# Generated by FakeRAM 2.0 (routing-friendly)
VERSION 5.7 ;
BUSBITCHARS "[]" ;
PROPERTYDEFINITIONS
  MACRO width INTEGER ;
  MACRO depth INTEGER ;
  MACRO banks INTEGER ;
END PROPERTYDEFINITIONS
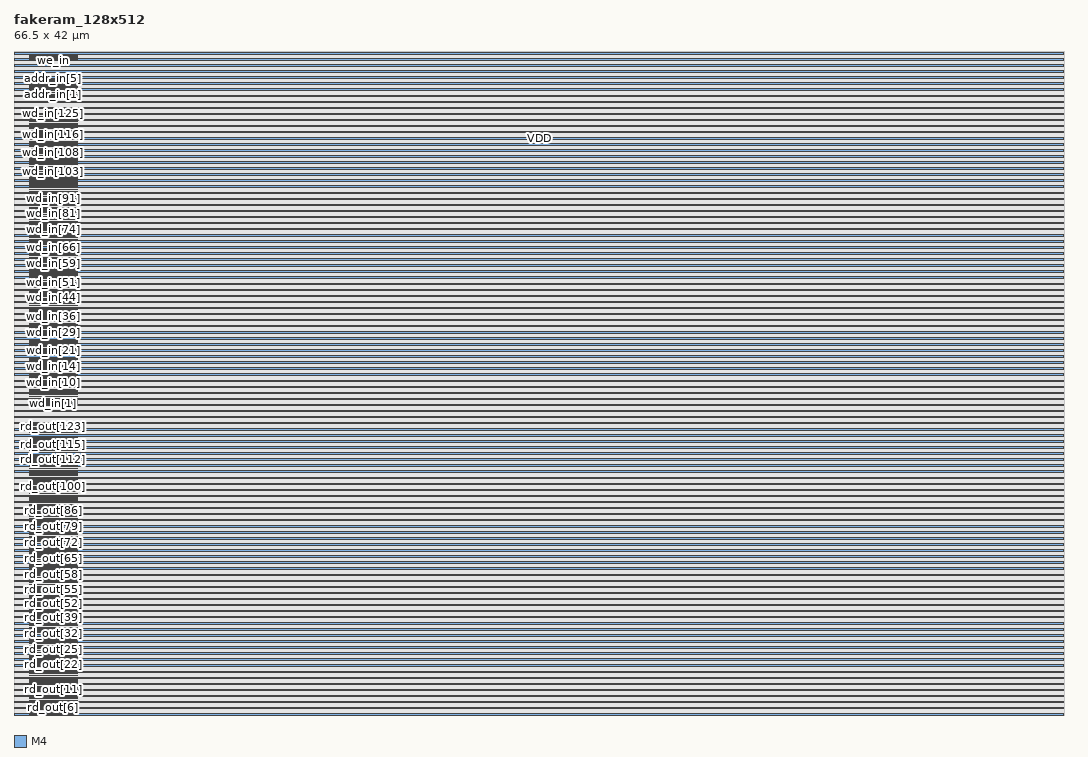
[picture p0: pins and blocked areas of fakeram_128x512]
MACRO fakeram_128x512
  PROPERTY width 128 ;
  PROPERTY depth 512 ;
  PROPERTY banks 4 ;
  FOREIGN fakeram_128x512 0 0 ;
  SYMMETRY X Y R90 ;
  SIZE 66.500 BY 42.000 ;
  CLASS BLOCK ;
  PIN rd_out[0]
    DIRECTION OUTPUT ;
    USE SIGNAL ;
    PORT
      LAYER M4 ;
      RECT 1.000 0.048 3.000 0.072 ;
    END
    PORT
      LAYER M4 ;
      RECT 1.000 0.036 4.000 0.084 ;
    END
  END rd_out[0]
  PIN rd_out[1]
    DIRECTION OUTPUT ;
    USE SIGNAL ;
    PORT
      LAYER M4 ;
      RECT 1.000 0.192 3.000 0.216 ;
    END
    PORT
      LAYER M4 ;
      RECT 1.000 0.180 4.000 0.228 ;
    END
  END rd_out[1]
  PIN rd_out[2]
    DIRECTION OUTPUT ;
    USE SIGNAL ;
    PORT
      LAYER M4 ;
      RECT 1.000 0.336 3.000 0.360 ;
    END
    PORT
      LAYER M4 ;
      RECT 1.000 0.324 4.000 0.372 ;
    END
  END rd_out[2]
  PIN rd_out[3]
    DIRECTION OUTPUT ;
    USE SIGNAL ;
    PORT
      LAYER M4 ;
      RECT 1.000 0.480 3.000 0.504 ;
    END
    PORT
      LAYER M4 ;
      RECT 1.000 0.468 4.000 0.516 ;
    END
  END rd_out[3]
  PIN rd_out[4]
    DIRECTION OUTPUT ;
    USE SIGNAL ;
    PORT
      LAYER M4 ;
      RECT 1.000 0.624 3.000 0.648 ;
    END
    PORT
      LAYER M4 ;
      RECT 1.000 0.612 4.000 0.660 ;
    END
  END rd_out[4]
  PIN rd_out[5]
    DIRECTION OUTPUT ;
    USE SIGNAL ;
    PORT
      LAYER M4 ;
      RECT 1.000 0.768 3.000 0.792 ;
    END
    PORT
      LAYER M4 ;
      RECT 1.000 0.756 4.000 0.804 ;
    END
  END rd_out[5]
  PIN rd_out[6]
    DIRECTION OUTPUT ;
    USE SIGNAL ;
    PORT
      LAYER M4 ;
      RECT 1.000 0.912 3.000 0.936 ;
    END
    PORT
      LAYER M4 ;
      RECT 1.000 0.900 4.000 0.948 ;
    END
  END rd_out[6]
  PIN rd_out[7]
    DIRECTION OUTPUT ;
    USE SIGNAL ;
    PORT
      LAYER M4 ;
      RECT 1.000 1.056 3.000 1.080 ;
    END
    PORT
      LAYER M4 ;
      RECT 1.000 1.044 4.000 1.092 ;
    END
  END rd_out[7]
  PIN rd_out[8]
    DIRECTION OUTPUT ;
    USE SIGNAL ;
    PORT
      LAYER M4 ;
      RECT 1.000 1.200 3.000 1.224 ;
    END
    PORT
      LAYER M4 ;
      RECT 1.000 1.188 4.000 1.236 ;
    END
  END rd_out[8]
  PIN rd_out[9]
    DIRECTION OUTPUT ;
    USE SIGNAL ;
    PORT
      LAYER M4 ;
      RECT 1.000 1.344 3.000 1.368 ;
    END
    PORT
      LAYER M4 ;
      RECT 1.000 1.332 4.000 1.380 ;
    END
  END rd_out[9]
  PIN rd_out[10]
    DIRECTION OUTPUT ;
    USE SIGNAL ;
    PORT
      LAYER M4 ;
      RECT 1.000 1.488 3.000 1.512 ;
    END
    PORT
      LAYER M4 ;
      RECT 1.000 1.476 4.000 1.524 ;
    END
  END rd_out[10]
  PIN rd_out[11]
    DIRECTION OUTPUT ;
    USE SIGNAL ;
    PORT
      LAYER M4 ;
      RECT 1.000 1.632 3.000 1.656 ;
    END
    PORT
      LAYER M4 ;
      RECT 1.000 1.620 4.000 1.668 ;
    END
  END rd_out[11]
  PIN rd_out[12]
    DIRECTION OUTPUT ;
    USE SIGNAL ;
    PORT
      LAYER M4 ;
      RECT 1.000 1.776 3.000 1.800 ;
    END
    PORT
      LAYER M4 ;
      RECT 1.000 1.764 4.000 1.812 ;
    END
  END rd_out[12]
  PIN rd_out[13]
    DIRECTION OUTPUT ;
    USE SIGNAL ;
    PORT
      LAYER M4 ;
      RECT 1.000 1.920 3.000 1.944 ;
    END
    PORT
      LAYER M4 ;
      RECT 1.000 1.908 4.000 1.956 ;
    END
  END rd_out[13]
  PIN rd_out[14]
    DIRECTION OUTPUT ;
    USE SIGNAL ;
    PORT
      LAYER M4 ;
      RECT 1.000 2.064 3.000 2.088 ;
    END
    PORT
      LAYER M4 ;
      RECT 1.000 2.052 4.000 2.100 ;
    END
  END rd_out[14]
  PIN rd_out[15]
    DIRECTION OUTPUT ;
    USE SIGNAL ;
    PORT
      LAYER M4 ;
      RECT 1.000 2.208 3.000 2.232 ;
    END
    PORT
      LAYER M4 ;
      RECT 1.000 2.196 4.000 2.244 ;
    END
  END rd_out[15]
  PIN rd_out[16]
    DIRECTION OUTPUT ;
    USE SIGNAL ;
    PORT
      LAYER M4 ;
      RECT 1.000 2.352 3.000 2.376 ;
    END
    PORT
      LAYER M4 ;
      RECT 1.000 2.340 4.000 2.388 ;
    END
  END rd_out[16]
  PIN rd_out[17]
    DIRECTION OUTPUT ;
    USE SIGNAL ;
    PORT
      LAYER M4 ;
      RECT 1.000 2.496 3.000 2.520 ;
    END
    PORT
      LAYER M4 ;
      RECT 1.000 2.484 4.000 2.532 ;
    END
  END rd_out[17]
  PIN rd_out[18]
    DIRECTION OUTPUT ;
    USE SIGNAL ;
    PORT
      LAYER M4 ;
      RECT 1.000 2.640 3.000 2.664 ;
    END
    PORT
      LAYER M4 ;
      RECT 1.000 2.628 4.000 2.676 ;
    END
  END rd_out[18]
  PIN rd_out[19]
    DIRECTION OUTPUT ;
    USE SIGNAL ;
    PORT
      LAYER M4 ;
      RECT 1.000 2.784 3.000 2.808 ;
    END
    PORT
      LAYER M4 ;
      RECT 1.000 2.772 4.000 2.820 ;
    END
  END rd_out[19]
  PIN rd_out[20]
    DIRECTION OUTPUT ;
    USE SIGNAL ;
    PORT
      LAYER M4 ;
      RECT 1.000 2.928 3.000 2.952 ;
    END
    PORT
      LAYER M4 ;
      RECT 1.000 2.916 4.000 2.964 ;
    END
  END rd_out[20]
  PIN rd_out[21]
    DIRECTION OUTPUT ;
    USE SIGNAL ;
    PORT
      LAYER M4 ;
      RECT 1.000 3.072 3.000 3.096 ;
    END
    PORT
      LAYER M4 ;
      RECT 1.000 3.060 4.000 3.108 ;
    END
  END rd_out[21]
  PIN rd_out[22]
    DIRECTION OUTPUT ;
    USE SIGNAL ;
    PORT
      LAYER M4 ;
      RECT 1.000 3.216 3.000 3.240 ;
    END
    PORT
      LAYER M4 ;
      RECT 1.000 3.204 4.000 3.252 ;
    END
  END rd_out[22]
  PIN rd_out[23]
    DIRECTION OUTPUT ;
    USE SIGNAL ;
    PORT
      LAYER M4 ;
      RECT 1.000 3.360 3.000 3.384 ;
    END
    PORT
      LAYER M4 ;
      RECT 1.000 3.348 4.000 3.396 ;
    END
  END rd_out[23]
  PIN rd_out[24]
    DIRECTION OUTPUT ;
    USE SIGNAL ;
    PORT
      LAYER M4 ;
      RECT 1.000 3.504 3.000 3.528 ;
    END
    PORT
      LAYER M4 ;
      RECT 1.000 3.492 4.000 3.540 ;
    END
  END rd_out[24]
  PIN rd_out[25]
    DIRECTION OUTPUT ;
    USE SIGNAL ;
    PORT
      LAYER M4 ;
      RECT 1.000 3.648 3.000 3.672 ;
    END
    PORT
      LAYER M4 ;
      RECT 1.000 3.636 4.000 3.684 ;
    END
  END rd_out[25]
  PIN rd_out[26]
    DIRECTION OUTPUT ;
    USE SIGNAL ;
    PORT
      LAYER M4 ;
      RECT 1.000 3.792 3.000 3.816 ;
    END
    PORT
      LAYER M4 ;
      RECT 1.000 3.780 4.000 3.828 ;
    END
  END rd_out[26]
  PIN rd_out[27]
    DIRECTION OUTPUT ;
    USE SIGNAL ;
    PORT
      LAYER M4 ;
      RECT 1.000 3.936 3.000 3.960 ;
    END
    PORT
      LAYER M4 ;
      RECT 1.000 3.924 4.000 3.972 ;
    END
  END rd_out[27]
  PIN rd_out[28]
    DIRECTION OUTPUT ;
    USE SIGNAL ;
    PORT
      LAYER M4 ;
      RECT 1.000 4.080 3.000 4.104 ;
    END
    PORT
      LAYER M4 ;
      RECT 1.000 4.068 4.000 4.116 ;
    END
  END rd_out[28]
  PIN rd_out[29]
    DIRECTION OUTPUT ;
    USE SIGNAL ;
    PORT
      LAYER M4 ;
      RECT 1.000 4.224 3.000 4.248 ;
    END
    PORT
      LAYER M4 ;
      RECT 1.000 4.212 4.000 4.260 ;
    END
  END rd_out[29]
  PIN rd_out[30]
    DIRECTION OUTPUT ;
    USE SIGNAL ;
    PORT
      LAYER M4 ;
      RECT 1.000 4.368 3.000 4.392 ;
    END
    PORT
      LAYER M4 ;
      RECT 1.000 4.356 4.000 4.404 ;
    END
  END rd_out[30]
  PIN rd_out[31]
    DIRECTION OUTPUT ;
    USE SIGNAL ;
    PORT
      LAYER M4 ;
      RECT 1.000 4.512 3.000 4.536 ;
    END
    PORT
      LAYER M4 ;
      RECT 1.000 4.500 4.000 4.548 ;
    END
  END rd_out[31]
  PIN rd_out[32]
    DIRECTION OUTPUT ;
    USE SIGNAL ;
    PORT
      LAYER M4 ;
      RECT 1.000 4.656 3.000 4.680 ;
    END
    PORT
      LAYER M4 ;
      RECT 1.000 4.644 4.000 4.692 ;
    END
  END rd_out[32]
  PIN rd_out[33]
    DIRECTION OUTPUT ;
    USE SIGNAL ;
    PORT
      LAYER M4 ;
      RECT 1.000 4.800 3.000 4.824 ;
    END
    PORT
      LAYER M4 ;
      RECT 1.000 4.788 4.000 4.836 ;
    END
  END rd_out[33]
  PIN rd_out[34]
    DIRECTION OUTPUT ;
    USE SIGNAL ;
    PORT
      LAYER M4 ;
      RECT 1.000 4.944 3.000 4.968 ;
    END
    PORT
      LAYER M4 ;
      RECT 1.000 4.932 4.000 4.980 ;
    END
  END rd_out[34]
  PIN rd_out[35]
    DIRECTION OUTPUT ;
    USE SIGNAL ;
    PORT
      LAYER M4 ;
      RECT 1.000 5.088 3.000 5.112 ;
    END
    PORT
      LAYER M4 ;
      RECT 1.000 5.076 4.000 5.124 ;
    END
  END rd_out[35]
  PIN rd_out[36]
    DIRECTION OUTPUT ;
    USE SIGNAL ;
    PORT
      LAYER M4 ;
      RECT 1.000 5.232 3.000 5.256 ;
    END
    PORT
      LAYER M4 ;
      RECT 1.000 5.220 4.000 5.268 ;
    END
  END rd_out[36]
  PIN rd_out[37]
    DIRECTION OUTPUT ;
    USE SIGNAL ;
    PORT
      LAYER M4 ;
      RECT 1.000 5.376 3.000 5.400 ;
    END
    PORT
      LAYER M4 ;
      RECT 1.000 5.364 4.000 5.412 ;
    END
  END rd_out[37]
  PIN rd_out[38]
    DIRECTION OUTPUT ;
    USE SIGNAL ;
    PORT
      LAYER M4 ;
      RECT 1.000 5.520 3.000 5.544 ;
    END
    PORT
      LAYER M4 ;
      RECT 1.000 5.508 4.000 5.556 ;
    END
  END rd_out[38]
  PIN rd_out[39]
    DIRECTION OUTPUT ;
    USE SIGNAL ;
    PORT
      LAYER M4 ;
      RECT 1.000 5.664 3.000 5.688 ;
    END
    PORT
      LAYER M4 ;
      RECT 1.000 5.652 4.000 5.700 ;
    END
  END rd_out[39]
  PIN rd_out[40]
    DIRECTION OUTPUT ;
    USE SIGNAL ;
    PORT
      LAYER M4 ;
      RECT 1.000 5.808 3.000 5.832 ;
    END
    PORT
      LAYER M4 ;
      RECT 1.000 5.796 4.000 5.844 ;
    END
  END rd_out[40]
  PIN rd_out[41]
    DIRECTION OUTPUT ;
    USE SIGNAL ;
    PORT
      LAYER M4 ;
      RECT 1.000 5.952 3.000 5.976 ;
    END
    PORT
      LAYER M4 ;
      RECT 1.000 5.940 4.000 5.988 ;
    END
  END rd_out[41]
  PIN rd_out[42]
    DIRECTION OUTPUT ;
    USE SIGNAL ;
    PORT
      LAYER M4 ;
      RECT 1.000 6.096 3.000 6.120 ;
    END
    PORT
      LAYER M4 ;
      RECT 1.000 6.084 4.000 6.132 ;
    END
  END rd_out[42]
  PIN rd_out[43]
    DIRECTION OUTPUT ;
    USE SIGNAL ;
    PORT
      LAYER M4 ;
      RECT 1.000 6.240 3.000 6.264 ;
    END
    PORT
      LAYER M4 ;
      RECT 1.000 6.228 4.000 6.276 ;
    END
  END rd_out[43]
  PIN rd_out[44]
    DIRECTION OUTPUT ;
    USE SIGNAL ;
    PORT
      LAYER M4 ;
      RECT 1.000 6.384 3.000 6.408 ;
    END
    PORT
      LAYER M4 ;
      RECT 1.000 6.372 4.000 6.420 ;
    END
  END rd_out[44]
  PIN rd_out[45]
    DIRECTION OUTPUT ;
    USE SIGNAL ;
    PORT
      LAYER M4 ;
      RECT 1.000 6.528 3.000 6.552 ;
    END
    PORT
      LAYER M4 ;
      RECT 1.000 6.516 4.000 6.564 ;
    END
  END rd_out[45]
  PIN rd_out[46]
    DIRECTION OUTPUT ;
    USE SIGNAL ;
    PORT
      LAYER M4 ;
      RECT 1.000 6.672 3.000 6.696 ;
    END
    PORT
      LAYER M4 ;
      RECT 1.000 6.660 4.000 6.708 ;
    END
  END rd_out[46]
  PIN rd_out[47]
    DIRECTION OUTPUT ;
    USE SIGNAL ;
    PORT
      LAYER M4 ;
      RECT 1.000 6.816 3.000 6.840 ;
    END
    PORT
      LAYER M4 ;
      RECT 1.000 6.804 4.000 6.852 ;
    END
  END rd_out[47]
  PIN rd_out[48]
    DIRECTION OUTPUT ;
    USE SIGNAL ;
    PORT
      LAYER M4 ;
      RECT 1.000 6.960 3.000 6.984 ;
    END
    PORT
      LAYER M4 ;
      RECT 1.000 6.948 4.000 6.996 ;
    END
  END rd_out[48]
  PIN rd_out[49]
    DIRECTION OUTPUT ;
    USE SIGNAL ;
    PORT
      LAYER M4 ;
      RECT 1.000 7.104 3.000 7.128 ;
    END
    PORT
      LAYER M4 ;
      RECT 1.000 7.092 4.000 7.140 ;
    END
  END rd_out[49]
  PIN rd_out[50]
    DIRECTION OUTPUT ;
    USE SIGNAL ;
    PORT
      LAYER M4 ;
      RECT 1.000 7.248 3.000 7.272 ;
    END
    PORT
      LAYER M4 ;
      RECT 1.000 7.236 4.000 7.284 ;
    END
  END rd_out[50]
  PIN rd_out[51]
    DIRECTION OUTPUT ;
    USE SIGNAL ;
    PORT
      LAYER M4 ;
      RECT 1.000 7.392 3.000 7.416 ;
    END
    PORT
      LAYER M4 ;
      RECT 1.000 7.380 4.000 7.428 ;
    END
  END rd_out[51]
  PIN rd_out[52]
    DIRECTION OUTPUT ;
    USE SIGNAL ;
    PORT
      LAYER M4 ;
      RECT 1.000 7.536 3.000 7.560 ;
    END
    PORT
      LAYER M4 ;
      RECT 1.000 7.524 4.000 7.572 ;
    END
  END rd_out[52]
  PIN rd_out[53]
    DIRECTION OUTPUT ;
    USE SIGNAL ;
    PORT
      LAYER M4 ;
      RECT 1.000 7.680 3.000 7.704 ;
    END
    PORT
      LAYER M4 ;
      RECT 1.000 7.668 4.000 7.716 ;
    END
  END rd_out[53]
  PIN rd_out[54]
    DIRECTION OUTPUT ;
    USE SIGNAL ;
    PORT
      LAYER M4 ;
      RECT 1.000 7.824 3.000 7.848 ;
    END
    PORT
      LAYER M4 ;
      RECT 1.000 7.812 4.000 7.860 ;
    END
  END rd_out[54]
  PIN rd_out[55]
    DIRECTION OUTPUT ;
    USE SIGNAL ;
    PORT
      LAYER M4 ;
      RECT 1.000 7.968 3.000 7.992 ;
    END
    PORT
      LAYER M4 ;
      RECT 1.000 7.956 4.000 8.004 ;
    END
  END rd_out[55]
  PIN rd_out[56]
    DIRECTION OUTPUT ;
    USE SIGNAL ;
    PORT
      LAYER M4 ;
      RECT 1.000 8.112 3.000 8.136 ;
    END
    PORT
      LAYER M4 ;
      RECT 1.000 8.100 4.000 8.148 ;
    END
  END rd_out[56]
  PIN rd_out[57]
    DIRECTION OUTPUT ;
    USE SIGNAL ;
    PORT
      LAYER M4 ;
      RECT 1.000 8.256 3.000 8.280 ;
    END
    PORT
      LAYER M4 ;
      RECT 1.000 8.244 4.000 8.292 ;
    END
  END rd_out[57]
  PIN rd_out[58]
    DIRECTION OUTPUT ;
    USE SIGNAL ;
    PORT
      LAYER M4 ;
      RECT 1.000 8.400 3.000 8.424 ;
    END
    PORT
      LAYER M4 ;
      RECT 1.000 8.388 4.000 8.436 ;
    END
  END rd_out[58]
  PIN rd_out[59]
    DIRECTION OUTPUT ;
    USE SIGNAL ;
    PORT
      LAYER M4 ;
      RECT 1.000 8.544 3.000 8.568 ;
    END
    PORT
      LAYER M4 ;
      RECT 1.000 8.532 4.000 8.580 ;
    END
  END rd_out[59]
  PIN rd_out[60]
    DIRECTION OUTPUT ;
    USE SIGNAL ;
    PORT
      LAYER M4 ;
      RECT 1.000 8.688 3.000 8.712 ;
    END
    PORT
      LAYER M4 ;
      RECT 1.000 8.676 4.000 8.724 ;
    END
  END rd_out[60]
  PIN rd_out[61]
    DIRECTION OUTPUT ;
    USE SIGNAL ;
    PORT
      LAYER M4 ;
      RECT 1.000 8.832 3.000 8.856 ;
    END
    PORT
      LAYER M4 ;
      RECT 1.000 8.820 4.000 8.868 ;
    END
  END rd_out[61]
  PIN rd_out[62]
    DIRECTION OUTPUT ;
    USE SIGNAL ;
    PORT
      LAYER M4 ;
      RECT 1.000 8.976 3.000 9.000 ;
    END
    PORT
      LAYER M4 ;
      RECT 1.000 8.964 4.000 9.012 ;
    END
  END rd_out[62]
  PIN rd_out[63]
    DIRECTION OUTPUT ;
    USE SIGNAL ;
    PORT
      LAYER M4 ;
      RECT 1.000 9.120 3.000 9.144 ;
    END
    PORT
      LAYER M4 ;
      RECT 1.000 9.108 4.000 9.156 ;
    END
  END rd_out[63]
  PIN rd_out[64]
    DIRECTION OUTPUT ;
    USE SIGNAL ;
    PORT
      LAYER M4 ;
      RECT 1.000 9.264 3.000 9.288 ;
    END
    PORT
      LAYER M4 ;
      RECT 1.000 9.252 4.000 9.300 ;
    END
  END rd_out[64]
  PIN rd_out[65]
    DIRECTION OUTPUT ;
    USE SIGNAL ;
    PORT
      LAYER M4 ;
      RECT 1.000 9.408 3.000 9.432 ;
    END
    PORT
      LAYER M4 ;
      RECT 1.000 9.396 4.000 9.444 ;
    END
  END rd_out[65]
  PIN rd_out[66]
    DIRECTION OUTPUT ;
    USE SIGNAL ;
    PORT
      LAYER M4 ;
      RECT 1.000 9.552 3.000 9.576 ;
    END
    PORT
      LAYER M4 ;
      RECT 1.000 9.540 4.000 9.588 ;
    END
  END rd_out[66]
  PIN rd_out[67]
    DIRECTION OUTPUT ;
    USE SIGNAL ;
    PORT
      LAYER M4 ;
      RECT 1.000 9.696 3.000 9.720 ;
    END
    PORT
      LAYER M4 ;
      RECT 1.000 9.684 4.000 9.732 ;
    END
  END rd_out[67]
  PIN rd_out[68]
    DIRECTION OUTPUT ;
    USE SIGNAL ;
    PORT
      LAYER M4 ;
      RECT 1.000 9.840 3.000 9.864 ;
    END
    PORT
      LAYER M4 ;
      RECT 1.000 9.828 4.000 9.876 ;
    END
  END rd_out[68]
  PIN rd_out[69]
    DIRECTION OUTPUT ;
    USE SIGNAL ;
    PORT
      LAYER M4 ;
      RECT 1.000 9.984 3.000 10.008 ;
    END
    PORT
      LAYER M4 ;
      RECT 1.000 9.972 4.000 10.020 ;
    END
  END rd_out[69]
  PIN rd_out[70]
    DIRECTION OUTPUT ;
    USE SIGNAL ;
    PORT
      LAYER M4 ;
      RECT 1.000 10.128 3.000 10.152 ;
    END
    PORT
      LAYER M4 ;
      RECT 1.000 10.116 4.000 10.164 ;
    END
  END rd_out[70]
  PIN rd_out[71]
    DIRECTION OUTPUT ;
    USE SIGNAL ;
    PORT
      LAYER M4 ;
      RECT 1.000 10.272 3.000 10.296 ;
    END
    PORT
      LAYER M4 ;
      RECT 1.000 10.260 4.000 10.308 ;
    END
  END rd_out[71]
  PIN rd_out[72]
    DIRECTION OUTPUT ;
    USE SIGNAL ;
    PORT
      LAYER M4 ;
      RECT 1.000 10.416 3.000 10.440 ;
    END
    PORT
      LAYER M4 ;
      RECT 1.000 10.404 4.000 10.452 ;
    END
  END rd_out[72]
  PIN rd_out[73]
    DIRECTION OUTPUT ;
    USE SIGNAL ;
    PORT
      LAYER M4 ;
      RECT 1.000 10.560 3.000 10.584 ;
    END
    PORT
      LAYER M4 ;
      RECT 1.000 10.548 4.000 10.596 ;
    END
  END rd_out[73]
  PIN rd_out[74]
    DIRECTION OUTPUT ;
    USE SIGNAL ;
    PORT
      LAYER M4 ;
      RECT 1.000 10.704 3.000 10.728 ;
    END
    PORT
      LAYER M4 ;
      RECT 1.000 10.692 4.000 10.740 ;
    END
  END rd_out[74]
  PIN rd_out[75]
    DIRECTION OUTPUT ;
    USE SIGNAL ;
    PORT
      LAYER M4 ;
      RECT 1.000 10.848 3.000 10.872 ;
    END
    PORT
      LAYER M4 ;
      RECT 1.000 10.836 4.000 10.884 ;
    END
  END rd_out[75]
  PIN rd_out[76]
    DIRECTION OUTPUT ;
    USE SIGNAL ;
    PORT
      LAYER M4 ;
      RECT 1.000 10.992 3.000 11.016 ;
    END
    PORT
      LAYER M4 ;
      RECT 1.000 10.980 4.000 11.028 ;
    END
  END rd_out[76]
  PIN rd_out[77]
    DIRECTION OUTPUT ;
    USE SIGNAL ;
    PORT
      LAYER M4 ;
      RECT 1.000 11.136 3.000 11.160 ;
    END
    PORT
      LAYER M4 ;
      RECT 1.000 11.124 4.000 11.172 ;
    END
  END rd_out[77]
  PIN rd_out[78]
    DIRECTION OUTPUT ;
    USE SIGNAL ;
    PORT
      LAYER M4 ;
      RECT 1.000 11.280 3.000 11.304 ;
    END
    PORT
      LAYER M4 ;
      RECT 1.000 11.268 4.000 11.316 ;
    END
  END rd_out[78]
  PIN rd_out[79]
    DIRECTION OUTPUT ;
    USE SIGNAL ;
    PORT
      LAYER M4 ;
      RECT 1.000 11.424 3.000 11.448 ;
    END
    PORT
      LAYER M4 ;
      RECT 1.000 11.412 4.000 11.460 ;
    END
  END rd_out[79]
  PIN rd_out[80]
    DIRECTION OUTPUT ;
    USE SIGNAL ;
    PORT
      LAYER M4 ;
      RECT 1.000 11.568 3.000 11.592 ;
    END
    PORT
      LAYER M4 ;
      RECT 1.000 11.556 4.000 11.604 ;
    END
  END rd_out[80]
  PIN rd_out[81]
    DIRECTION OUTPUT ;
    USE SIGNAL ;
    PORT
      LAYER M4 ;
      RECT 1.000 11.712 3.000 11.736 ;
    END
    PORT
      LAYER M4 ;
      RECT 1.000 11.700 4.000 11.748 ;
    END
  END rd_out[81]
  PIN rd_out[82]
    DIRECTION OUTPUT ;
    USE SIGNAL ;
    PORT
      LAYER M4 ;
      RECT 1.000 11.856 3.000 11.880 ;
    END
    PORT
      LAYER M4 ;
      RECT 1.000 11.844 4.000 11.892 ;
    END
  END rd_out[82]
  PIN rd_out[83]
    DIRECTION OUTPUT ;
    USE SIGNAL ;
    PORT
      LAYER M4 ;
      RECT 1.000 12.000 3.000 12.024 ;
    END
    PORT
      LAYER M4 ;
      RECT 1.000 11.988 4.000 12.036 ;
    END
  END rd_out[83]
  PIN rd_out[84]
    DIRECTION OUTPUT ;
    USE SIGNAL ;
    PORT
      LAYER M4 ;
      RECT 1.000 12.144 3.000 12.168 ;
    END
    PORT
      LAYER M4 ;
      RECT 1.000 12.132 4.000 12.180 ;
    END
  END rd_out[84]
  PIN rd_out[85]
    DIRECTION OUTPUT ;
    USE SIGNAL ;
    PORT
      LAYER M4 ;
      RECT 1.000 12.288 3.000 12.312 ;
    END
    PORT
      LAYER M4 ;
      RECT 1.000 12.276 4.000 12.324 ;
    END
  END rd_out[85]
  PIN rd_out[86]
    DIRECTION OUTPUT ;
    USE SIGNAL ;
    PORT
      LAYER M4 ;
      RECT 1.000 12.432 3.000 12.456 ;
    END
    PORT
      LAYER M4 ;
      RECT 1.000 12.420 4.000 12.468 ;
    END
  END rd_out[86]
  PIN rd_out[87]
    DIRECTION OUTPUT ;
    USE SIGNAL ;
    PORT
      LAYER M4 ;
      RECT 1.000 12.576 3.000 12.600 ;
    END
    PORT
      LAYER M4 ;
      RECT 1.000 12.564 4.000 12.612 ;
    END
  END rd_out[87]
  PIN rd_out[88]
    DIRECTION OUTPUT ;
    USE SIGNAL ;
    PORT
      LAYER M4 ;
      RECT 1.000 12.720 3.000 12.744 ;
    END
    PORT
      LAYER M4 ;
      RECT 1.000 12.708 4.000 12.756 ;
    END
  END rd_out[88]
  PIN rd_out[89]
    DIRECTION OUTPUT ;
    USE SIGNAL ;
    PORT
      LAYER M4 ;
      RECT 1.000 12.864 3.000 12.888 ;
    END
    PORT
      LAYER M4 ;
      RECT 1.000 12.852 4.000 12.900 ;
    END
  END rd_out[89]
  PIN rd_out[90]
    DIRECTION OUTPUT ;
    USE SIGNAL ;
    PORT
      LAYER M4 ;
      RECT 1.000 13.008 3.000 13.032 ;
    END
    PORT
      LAYER M4 ;
      RECT 1.000 12.996 4.000 13.044 ;
    END
  END rd_out[90]
  PIN rd_out[91]
    DIRECTION OUTPUT ;
    USE SIGNAL ;
    PORT
      LAYER M4 ;
      RECT 1.000 13.152 3.000 13.176 ;
    END
    PORT
      LAYER M4 ;
      RECT 1.000 13.140 4.000 13.188 ;
    END
  END rd_out[91]
  PIN rd_out[92]
    DIRECTION OUTPUT ;
    USE SIGNAL ;
    PORT
      LAYER M4 ;
      RECT 1.000 13.296 3.000 13.320 ;
    END
    PORT
      LAYER M4 ;
      RECT 1.000 13.284 4.000 13.332 ;
    END
  END rd_out[92]
  PIN rd_out[93]
    DIRECTION OUTPUT ;
    USE SIGNAL ;
    PORT
      LAYER M4 ;
      RECT 1.000 13.440 3.000 13.464 ;
    END
    PORT
      LAYER M4 ;
      RECT 1.000 13.428 4.000 13.476 ;
    END
  END rd_out[93]
  PIN rd_out[94]
    DIRECTION OUTPUT ;
    USE SIGNAL ;
    PORT
      LAYER M4 ;
      RECT 1.000 13.584 3.000 13.608 ;
    END
    PORT
      LAYER M4 ;
      RECT 1.000 13.572 4.000 13.620 ;
    END
  END rd_out[94]
  PIN rd_out[95]
    DIRECTION OUTPUT ;
    USE SIGNAL ;
    PORT
      LAYER M4 ;
      RECT 1.000 13.728 3.000 13.752 ;
    END
    PORT
      LAYER M4 ;
      RECT 1.000 13.716 4.000 13.764 ;
    END
  END rd_out[95]
  PIN rd_out[96]
    DIRECTION OUTPUT ;
    USE SIGNAL ;
    PORT
      LAYER M4 ;
      RECT 1.000 13.872 3.000 13.896 ;
    END
    PORT
      LAYER M4 ;
      RECT 1.000 13.860 4.000 13.908 ;
    END
  END rd_out[96]
  PIN rd_out[97]
    DIRECTION OUTPUT ;
    USE SIGNAL ;
    PORT
      LAYER M4 ;
      RECT 1.000 14.016 3.000 14.040 ;
    END
    PORT
      LAYER M4 ;
      RECT 1.000 14.004 4.000 14.052 ;
    END
  END rd_out[97]
  PIN rd_out[98]
    DIRECTION OUTPUT ;
    USE SIGNAL ;
    PORT
      LAYER M4 ;
      RECT 1.000 14.160 3.000 14.184 ;
    END
    PORT
      LAYER M4 ;
      RECT 1.000 14.148 4.000 14.196 ;
    END
  END rd_out[98]
  PIN rd_out[99]
    DIRECTION OUTPUT ;
    USE SIGNAL ;
    PORT
      LAYER M4 ;
      RECT 1.000 14.304 3.000 14.328 ;
    END
    PORT
      LAYER M4 ;
      RECT 1.000 14.292 4.000 14.340 ;
    END
  END rd_out[99]
  PIN rd_out[100]
    DIRECTION OUTPUT ;
    USE SIGNAL ;
    PORT
      LAYER M4 ;
      RECT 1.000 14.448 3.000 14.472 ;
    END
    PORT
      LAYER M4 ;
      RECT 1.000 14.436 4.000 14.484 ;
    END
  END rd_out[100]
  PIN rd_out[101]
    DIRECTION OUTPUT ;
    USE SIGNAL ;
    PORT
      LAYER M4 ;
      RECT 1.000 14.592 3.000 14.616 ;
    END
    PORT
      LAYER M4 ;
      RECT 1.000 14.580 4.000 14.628 ;
    END
  END rd_out[101]
  PIN rd_out[102]
    DIRECTION OUTPUT ;
    USE SIGNAL ;
    PORT
      LAYER M4 ;
      RECT 1.000 14.736 3.000 14.760 ;
    END
    PORT
      LAYER M4 ;
      RECT 1.000 14.724 4.000 14.772 ;
    END
  END rd_out[102]
  PIN rd_out[103]
    DIRECTION OUTPUT ;
    USE SIGNAL ;
    PORT
      LAYER M4 ;
      RECT 1.000 14.880 3.000 14.904 ;
    END
    PORT
      LAYER M4 ;
      RECT 1.000 14.868 4.000 14.916 ;
    END
  END rd_out[103]
  PIN rd_out[104]
    DIRECTION OUTPUT ;
    USE SIGNAL ;
    PORT
      LAYER M4 ;
      RECT 1.000 15.024 3.000 15.048 ;
    END
    PORT
      LAYER M4 ;
      RECT 1.000 15.012 4.000 15.060 ;
    END
  END rd_out[104]
  PIN rd_out[105]
    DIRECTION OUTPUT ;
    USE SIGNAL ;
    PORT
      LAYER M4 ;
      RECT 1.000 15.168 3.000 15.192 ;
    END
    PORT
      LAYER M4 ;
      RECT 1.000 15.156 4.000 15.204 ;
    END
  END rd_out[105]
  PIN rd_out[106]
    DIRECTION OUTPUT ;
    USE SIGNAL ;
    PORT
      LAYER M4 ;
      RECT 1.000 15.312 3.000 15.336 ;
    END
    PORT
      LAYER M4 ;
      RECT 1.000 15.300 4.000 15.348 ;
    END
  END rd_out[106]
  PIN rd_out[107]
    DIRECTION OUTPUT ;
    USE SIGNAL ;
    PORT
      LAYER M4 ;
      RECT 1.000 15.456 3.000 15.480 ;
    END
    PORT
      LAYER M4 ;
      RECT 1.000 15.444 4.000 15.492 ;
    END
  END rd_out[107]
  PIN rd_out[108]
    DIRECTION OUTPUT ;
    USE SIGNAL ;
    PORT
      LAYER M4 ;
      RECT 1.000 15.600 3.000 15.624 ;
    END
    PORT
      LAYER M4 ;
      RECT 1.000 15.588 4.000 15.636 ;
    END
  END rd_out[108]
  PIN rd_out[109]
    DIRECTION OUTPUT ;
    USE SIGNAL ;
    PORT
      LAYER M4 ;
      RECT 1.000 15.744 3.000 15.768 ;
    END
    PORT
      LAYER M4 ;
      RECT 1.000 15.732 4.000 15.780 ;
    END
  END rd_out[109]
  PIN rd_out[110]
    DIRECTION OUTPUT ;
    USE SIGNAL ;
    PORT
      LAYER M4 ;
      RECT 1.000 15.888 3.000 15.912 ;
    END
    PORT
      LAYER M4 ;
      RECT 1.000 15.876 4.000 15.924 ;
    END
  END rd_out[110]
  PIN rd_out[111]
    DIRECTION OUTPUT ;
    USE SIGNAL ;
    PORT
      LAYER M4 ;
      RECT 1.000 16.032 3.000 16.056 ;
    END
    PORT
      LAYER M4 ;
      RECT 1.000 16.020 4.000 16.068 ;
    END
  END rd_out[111]
  PIN rd_out[112]
    DIRECTION OUTPUT ;
    USE SIGNAL ;
    PORT
      LAYER M4 ;
      RECT 1.000 16.176 3.000 16.200 ;
    END
    PORT
      LAYER M4 ;
      RECT 1.000 16.164 4.000 16.212 ;
    END
  END rd_out[112]
  PIN rd_out[113]
    DIRECTION OUTPUT ;
    USE SIGNAL ;
    PORT
      LAYER M4 ;
      RECT 1.000 16.320 3.000 16.344 ;
    END
    PORT
      LAYER M4 ;
      RECT 1.000 16.308 4.000 16.356 ;
    END
  END rd_out[113]
  PIN rd_out[114]
    DIRECTION OUTPUT ;
    USE SIGNAL ;
    PORT
      LAYER M4 ;
      RECT 1.000 16.464 3.000 16.488 ;
    END
    PORT
      LAYER M4 ;
      RECT 1.000 16.452 4.000 16.500 ;
    END
  END rd_out[114]
  PIN rd_out[115]
    DIRECTION OUTPUT ;
    USE SIGNAL ;
    PORT
      LAYER M4 ;
      RECT 1.000 16.608 3.000 16.632 ;
    END
    PORT
      LAYER M4 ;
      RECT 1.000 16.596 4.000 16.644 ;
    END
  END rd_out[115]
  PIN rd_out[116]
    DIRECTION OUTPUT ;
    USE SIGNAL ;
    PORT
      LAYER M4 ;
      RECT 1.000 16.752 3.000 16.776 ;
    END
    PORT
      LAYER M4 ;
      RECT 1.000 16.740 4.000 16.788 ;
    END
  END rd_out[116]
  PIN rd_out[117]
    DIRECTION OUTPUT ;
    USE SIGNAL ;
    PORT
      LAYER M4 ;
      RECT 1.000 16.896 3.000 16.920 ;
    END
    PORT
      LAYER M4 ;
      RECT 1.000 16.884 4.000 16.932 ;
    END
  END rd_out[117]
  PIN rd_out[118]
    DIRECTION OUTPUT ;
    USE SIGNAL ;
    PORT
      LAYER M4 ;
      RECT 1.000 17.040 3.000 17.064 ;
    END
    PORT
      LAYER M4 ;
      RECT 1.000 17.028 4.000 17.076 ;
    END
  END rd_out[118]
  PIN rd_out[119]
    DIRECTION OUTPUT ;
    USE SIGNAL ;
    PORT
      LAYER M4 ;
      RECT 1.000 17.184 3.000 17.208 ;
    END
    PORT
      LAYER M4 ;
      RECT 1.000 17.172 4.000 17.220 ;
    END
  END rd_out[119]
  PIN rd_out[120]
    DIRECTION OUTPUT ;
    USE SIGNAL ;
    PORT
      LAYER M4 ;
      RECT 1.000 17.328 3.000 17.352 ;
    END
    PORT
      LAYER M4 ;
      RECT 1.000 17.316 4.000 17.364 ;
    END
  END rd_out[120]
  PIN rd_out[121]
    DIRECTION OUTPUT ;
    USE SIGNAL ;
    PORT
      LAYER M4 ;
      RECT 1.000 17.472 3.000 17.496 ;
    END
    PORT
      LAYER M4 ;
      RECT 1.000 17.460 4.000 17.508 ;
    END
  END rd_out[121]
  PIN rd_out[122]
    DIRECTION OUTPUT ;
    USE SIGNAL ;
    PORT
      LAYER M4 ;
      RECT 1.000 17.616 3.000 17.640 ;
    END
    PORT
      LAYER M4 ;
      RECT 1.000 17.604 4.000 17.652 ;
    END
  END rd_out[122]
  PIN rd_out[123]
    DIRECTION OUTPUT ;
    USE SIGNAL ;
    PORT
      LAYER M4 ;
      RECT 1.000 17.760 3.000 17.784 ;
    END
    PORT
      LAYER M4 ;
      RECT 1.000 17.748 4.000 17.796 ;
    END
  END rd_out[123]
  PIN rd_out[124]
    DIRECTION OUTPUT ;
    USE SIGNAL ;
    PORT
      LAYER M4 ;
      RECT 1.000 17.904 3.000 17.928 ;
    END
    PORT
      LAYER M4 ;
      RECT 1.000 17.892 4.000 17.940 ;
    END
  END rd_out[124]
  PIN rd_out[125]
    DIRECTION OUTPUT ;
    USE SIGNAL ;
    PORT
      LAYER M4 ;
      RECT 1.000 18.048 3.000 18.072 ;
    END
    PORT
      LAYER M4 ;
      RECT 1.000 18.036 4.000 18.084 ;
    END
  END rd_out[125]
  PIN rd_out[126]
    DIRECTION OUTPUT ;
    USE SIGNAL ;
    PORT
      LAYER M4 ;
      RECT 1.000 18.192 3.000 18.216 ;
    END
    PORT
      LAYER M4 ;
      RECT 1.000 18.180 4.000 18.228 ;
    END
  END rd_out[126]
  PIN rd_out[127]
    DIRECTION OUTPUT ;
    USE SIGNAL ;
    PORT
      LAYER M4 ;
      RECT 1.000 18.336 3.000 18.360 ;
    END
    PORT
      LAYER M4 ;
      RECT 1.000 18.324 4.000 18.372 ;
    END
  END rd_out[127]
  PIN wd_in[0]
    DIRECTION INPUT ;
    USE SIGNAL ;
    PORT
      LAYER M4 ;
      RECT 1.000 19.584 3.000 19.608 ;
    END
    PORT
      LAYER M4 ;
      RECT 1.000 19.572 4.000 19.620 ;
    END
  END wd_in[0]
  PIN wd_in[1]
    DIRECTION INPUT ;
    USE SIGNAL ;
    PORT
      LAYER M4 ;
      RECT 1.000 19.728 3.000 19.752 ;
    END
    PORT
      LAYER M4 ;
      RECT 1.000 19.716 4.000 19.764 ;
    END
  END wd_in[1]
  PIN wd_in[2]
    DIRECTION INPUT ;
    USE SIGNAL ;
    PORT
      LAYER M4 ;
      RECT 1.000 19.872 3.000 19.896 ;
    END
    PORT
      LAYER M4 ;
      RECT 1.000 19.860 4.000 19.908 ;
    END
  END wd_in[2]
  PIN wd_in[3]
    DIRECTION INPUT ;
    USE SIGNAL ;
    PORT
      LAYER M4 ;
      RECT 1.000 20.016 3.000 20.040 ;
    END
    PORT
      LAYER M4 ;
      RECT 1.000 20.004 4.000 20.052 ;
    END
  END wd_in[3]
  PIN wd_in[4]
    DIRECTION INPUT ;
    USE SIGNAL ;
    PORT
      LAYER M4 ;
      RECT 1.000 20.160 3.000 20.184 ;
    END
    PORT
      LAYER M4 ;
      RECT 1.000 20.148 4.000 20.196 ;
    END
  END wd_in[4]
  PIN wd_in[5]
    DIRECTION INPUT ;
    USE SIGNAL ;
    PORT
      LAYER M4 ;
      RECT 1.000 20.304 3.000 20.328 ;
    END
    PORT
      LAYER M4 ;
      RECT 1.000 20.292 4.000 20.340 ;
    END
  END wd_in[5]
  PIN wd_in[6]
    DIRECTION INPUT ;
    USE SIGNAL ;
    PORT
      LAYER M4 ;
      RECT 1.000 20.448 3.000 20.472 ;
    END
    PORT
      LAYER M4 ;
      RECT 1.000 20.436 4.000 20.484 ;
    END
  END wd_in[6]
  PIN wd_in[7]
    DIRECTION INPUT ;
    USE SIGNAL ;
    PORT
      LAYER M4 ;
      RECT 1.000 20.592 3.000 20.616 ;
    END
    PORT
      LAYER M4 ;
      RECT 1.000 20.580 4.000 20.628 ;
    END
  END wd_in[7]
  PIN wd_in[8]
    DIRECTION INPUT ;
    USE SIGNAL ;
    PORT
      LAYER M4 ;
      RECT 1.000 20.736 3.000 20.760 ;
    END
    PORT
      LAYER M4 ;
      RECT 1.000 20.724 4.000 20.772 ;
    END
  END wd_in[8]
  PIN wd_in[9]
    DIRECTION INPUT ;
    USE SIGNAL ;
    PORT
      LAYER M4 ;
      RECT 1.000 20.880 3.000 20.904 ;
    END
    PORT
      LAYER M4 ;
      RECT 1.000 20.868 4.000 20.916 ;
    END
  END wd_in[9]
  PIN wd_in[10]
    DIRECTION INPUT ;
    USE SIGNAL ;
    PORT
      LAYER M4 ;
      RECT 1.000 21.024 3.000 21.048 ;
    END
    PORT
      LAYER M4 ;
      RECT 1.000 21.012 4.000 21.060 ;
    END
  END wd_in[10]
  PIN wd_in[11]
    DIRECTION INPUT ;
    USE SIGNAL ;
    PORT
      LAYER M4 ;
      RECT 1.000 21.168 3.000 21.192 ;
    END
    PORT
      LAYER M4 ;
      RECT 1.000 21.156 4.000 21.204 ;
    END
  END wd_in[11]
  PIN wd_in[12]
    DIRECTION INPUT ;
    USE SIGNAL ;
    PORT
      LAYER M4 ;
      RECT 1.000 21.312 3.000 21.336 ;
    END
    PORT
      LAYER M4 ;
      RECT 1.000 21.300 4.000 21.348 ;
    END
  END wd_in[12]
  PIN wd_in[13]
    DIRECTION INPUT ;
    USE SIGNAL ;
    PORT
      LAYER M4 ;
      RECT 1.000 21.456 3.000 21.480 ;
    END
    PORT
      LAYER M4 ;
      RECT 1.000 21.444 4.000 21.492 ;
    END
  END wd_in[13]
  PIN wd_in[14]
    DIRECTION INPUT ;
    USE SIGNAL ;
    PORT
      LAYER M4 ;
      RECT 1.000 21.600 3.000 21.624 ;
    END
    PORT
      LAYER M4 ;
      RECT 1.000 21.588 4.000 21.636 ;
    END
  END wd_in[14]
  PIN wd_in[15]
    DIRECTION INPUT ;
    USE SIGNAL ;
    PORT
      LAYER M4 ;
      RECT 1.000 21.744 3.000 21.768 ;
    END
    PORT
      LAYER M4 ;
      RECT 1.000 21.732 4.000 21.780 ;
    END
  END wd_in[15]
  PIN wd_in[16]
    DIRECTION INPUT ;
    USE SIGNAL ;
    PORT
      LAYER M4 ;
      RECT 1.000 21.888 3.000 21.912 ;
    END
    PORT
      LAYER M4 ;
      RECT 1.000 21.876 4.000 21.924 ;
    END
  END wd_in[16]
  PIN wd_in[17]
    DIRECTION INPUT ;
    USE SIGNAL ;
    PORT
      LAYER M4 ;
      RECT 1.000 22.032 3.000 22.056 ;
    END
    PORT
      LAYER M4 ;
      RECT 1.000 22.020 4.000 22.068 ;
    END
  END wd_in[17]
  PIN wd_in[18]
    DIRECTION INPUT ;
    USE SIGNAL ;
    PORT
      LAYER M4 ;
      RECT 1.000 22.176 3.000 22.200 ;
    END
    PORT
      LAYER M4 ;
      RECT 1.000 22.164 4.000 22.212 ;
    END
  END wd_in[18]
  PIN wd_in[19]
    DIRECTION INPUT ;
    USE SIGNAL ;
    PORT
      LAYER M4 ;
      RECT 1.000 22.320 3.000 22.344 ;
    END
    PORT
      LAYER M4 ;
      RECT 1.000 22.308 4.000 22.356 ;
    END
  END wd_in[19]
  PIN wd_in[20]
    DIRECTION INPUT ;
    USE SIGNAL ;
    PORT
      LAYER M4 ;
      RECT 1.000 22.464 3.000 22.488 ;
    END
    PORT
      LAYER M4 ;
      RECT 1.000 22.452 4.000 22.500 ;
    END
  END wd_in[20]
  PIN wd_in[21]
    DIRECTION INPUT ;
    USE SIGNAL ;
    PORT
      LAYER M4 ;
      RECT 1.000 22.608 3.000 22.632 ;
    END
    PORT
      LAYER M4 ;
      RECT 1.000 22.596 4.000 22.644 ;
    END
  END wd_in[21]
  PIN wd_in[22]
    DIRECTION INPUT ;
    USE SIGNAL ;
    PORT
      LAYER M4 ;
      RECT 1.000 22.752 3.000 22.776 ;
    END
    PORT
      LAYER M4 ;
      RECT 1.000 22.740 4.000 22.788 ;
    END
  END wd_in[22]
  PIN wd_in[23]
    DIRECTION INPUT ;
    USE SIGNAL ;
    PORT
      LAYER M4 ;
      RECT 1.000 22.896 3.000 22.920 ;
    END
    PORT
      LAYER M4 ;
      RECT 1.000 22.884 4.000 22.932 ;
    END
  END wd_in[23]
  PIN wd_in[24]
    DIRECTION INPUT ;
    USE SIGNAL ;
    PORT
      LAYER M4 ;
      RECT 1.000 23.040 3.000 23.064 ;
    END
    PORT
      LAYER M4 ;
      RECT 1.000 23.028 4.000 23.076 ;
    END
  END wd_in[24]
  PIN wd_in[25]
    DIRECTION INPUT ;
    USE SIGNAL ;
    PORT
      LAYER M4 ;
      RECT 1.000 23.184 3.000 23.208 ;
    END
    PORT
      LAYER M4 ;
      RECT 1.000 23.172 4.000 23.220 ;
    END
  END wd_in[25]
  PIN wd_in[26]
    DIRECTION INPUT ;
    USE SIGNAL ;
    PORT
      LAYER M4 ;
      RECT 1.000 23.328 3.000 23.352 ;
    END
    PORT
      LAYER M4 ;
      RECT 1.000 23.316 4.000 23.364 ;
    END
  END wd_in[26]
  PIN wd_in[27]
    DIRECTION INPUT ;
    USE SIGNAL ;
    PORT
      LAYER M4 ;
      RECT 1.000 23.472 3.000 23.496 ;
    END
    PORT
      LAYER M4 ;
      RECT 1.000 23.460 4.000 23.508 ;
    END
  END wd_in[27]
  PIN wd_in[28]
    DIRECTION INPUT ;
    USE SIGNAL ;
    PORT
      LAYER M4 ;
      RECT 1.000 23.616 3.000 23.640 ;
    END
    PORT
      LAYER M4 ;
      RECT 1.000 23.604 4.000 23.652 ;
    END
  END wd_in[28]
  PIN wd_in[29]
    DIRECTION INPUT ;
    USE SIGNAL ;
    PORT
      LAYER M4 ;
      RECT 1.000 23.760 3.000 23.784 ;
    END
    PORT
      LAYER M4 ;
      RECT 1.000 23.748 4.000 23.796 ;
    END
  END wd_in[29]
  PIN wd_in[30]
    DIRECTION INPUT ;
    USE SIGNAL ;
    PORT
      LAYER M4 ;
      RECT 1.000 23.904 3.000 23.928 ;
    END
    PORT
      LAYER M4 ;
      RECT 1.000 23.892 4.000 23.940 ;
    END
  END wd_in[30]
  PIN wd_in[31]
    DIRECTION INPUT ;
    USE SIGNAL ;
    PORT
      LAYER M4 ;
      RECT 1.000 24.048 3.000 24.072 ;
    END
    PORT
      LAYER M4 ;
      RECT 1.000 24.036 4.000 24.084 ;
    END
  END wd_in[31]
  PIN wd_in[32]
    DIRECTION INPUT ;
    USE SIGNAL ;
    PORT
      LAYER M4 ;
      RECT 1.000 24.192 3.000 24.216 ;
    END
    PORT
      LAYER M4 ;
      RECT 1.000 24.180 4.000 24.228 ;
    END
  END wd_in[32]
  PIN wd_in[33]
    DIRECTION INPUT ;
    USE SIGNAL ;
    PORT
      LAYER M4 ;
      RECT 1.000 24.336 3.000 24.360 ;
    END
    PORT
      LAYER M4 ;
      RECT 1.000 24.324 4.000 24.372 ;
    END
  END wd_in[33]
  PIN wd_in[34]
    DIRECTION INPUT ;
    USE SIGNAL ;
    PORT
      LAYER M4 ;
      RECT 1.000 24.480 3.000 24.504 ;
    END
    PORT
      LAYER M4 ;
      RECT 1.000 24.468 4.000 24.516 ;
    END
  END wd_in[34]
  PIN wd_in[35]
    DIRECTION INPUT ;
    USE SIGNAL ;
    PORT
      LAYER M4 ;
      RECT 1.000 24.624 3.000 24.648 ;
    END
    PORT
      LAYER M4 ;
      RECT 1.000 24.612 4.000 24.660 ;
    END
  END wd_in[35]
  PIN wd_in[36]
    DIRECTION INPUT ;
    USE SIGNAL ;
    PORT
      LAYER M4 ;
      RECT 1.000 24.768 3.000 24.792 ;
    END
    PORT
      LAYER M4 ;
      RECT 1.000 24.756 4.000 24.804 ;
    END
  END wd_in[36]
  PIN wd_in[37]
    DIRECTION INPUT ;
    USE SIGNAL ;
    PORT
      LAYER M4 ;
      RECT 1.000 24.912 3.000 24.936 ;
    END
    PORT
      LAYER M4 ;
      RECT 1.000 24.900 4.000 24.948 ;
    END
  END wd_in[37]
  PIN wd_in[38]
    DIRECTION INPUT ;
    USE SIGNAL ;
    PORT
      LAYER M4 ;
      RECT 1.000 25.056 3.000 25.080 ;
    END
    PORT
      LAYER M4 ;
      RECT 1.000 25.044 4.000 25.092 ;
    END
  END wd_in[38]
  PIN wd_in[39]
    DIRECTION INPUT ;
    USE SIGNAL ;
    PORT
      LAYER M4 ;
      RECT 1.000 25.200 3.000 25.224 ;
    END
    PORT
      LAYER M4 ;
      RECT 1.000 25.188 4.000 25.236 ;
    END
  END wd_in[39]
  PIN wd_in[40]
    DIRECTION INPUT ;
    USE SIGNAL ;
    PORT
      LAYER M4 ;
      RECT 1.000 25.344 3.000 25.368 ;
    END
    PORT
      LAYER M4 ;
      RECT 1.000 25.332 4.000 25.380 ;
    END
  END wd_in[40]
  PIN wd_in[41]
    DIRECTION INPUT ;
    USE SIGNAL ;
    PORT
      LAYER M4 ;
      RECT 1.000 25.488 3.000 25.512 ;
    END
    PORT
      LAYER M4 ;
      RECT 1.000 25.476 4.000 25.524 ;
    END
  END wd_in[41]
  PIN wd_in[42]
    DIRECTION INPUT ;
    USE SIGNAL ;
    PORT
      LAYER M4 ;
      RECT 1.000 25.632 3.000 25.656 ;
    END
    PORT
      LAYER M4 ;
      RECT 1.000 25.620 4.000 25.668 ;
    END
  END wd_in[42]
  PIN wd_in[43]
    DIRECTION INPUT ;
    USE SIGNAL ;
    PORT
      LAYER M4 ;
      RECT 1.000 25.776 3.000 25.800 ;
    END
    PORT
      LAYER M4 ;
      RECT 1.000 25.764 4.000 25.812 ;
    END
  END wd_in[43]
  PIN wd_in[44]
    DIRECTION INPUT ;
    USE SIGNAL ;
    PORT
      LAYER M4 ;
      RECT 1.000 25.920 3.000 25.944 ;
    END
    PORT
      LAYER M4 ;
      RECT 1.000 25.908 4.000 25.956 ;
    END
  END wd_in[44]
  PIN wd_in[45]
    DIRECTION INPUT ;
    USE SIGNAL ;
    PORT
      LAYER M4 ;
      RECT 1.000 26.064 3.000 26.088 ;
    END
    PORT
      LAYER M4 ;
      RECT 1.000 26.052 4.000 26.100 ;
    END
  END wd_in[45]
  PIN wd_in[46]
    DIRECTION INPUT ;
    USE SIGNAL ;
    PORT
      LAYER M4 ;
      RECT 1.000 26.208 3.000 26.232 ;
    END
    PORT
      LAYER M4 ;
      RECT 1.000 26.196 4.000 26.244 ;
    END
  END wd_in[46]
  PIN wd_in[47]
    DIRECTION INPUT ;
    USE SIGNAL ;
    PORT
      LAYER M4 ;
      RECT 1.000 26.352 3.000 26.376 ;
    END
    PORT
      LAYER M4 ;
      RECT 1.000 26.340 4.000 26.388 ;
    END
  END wd_in[47]
  PIN wd_in[48]
    DIRECTION INPUT ;
    USE SIGNAL ;
    PORT
      LAYER M4 ;
      RECT 1.000 26.496 3.000 26.520 ;
    END
    PORT
      LAYER M4 ;
      RECT 1.000 26.484 4.000 26.532 ;
    END
  END wd_in[48]
  PIN wd_in[49]
    DIRECTION INPUT ;
    USE SIGNAL ;
    PORT
      LAYER M4 ;
      RECT 1.000 26.640 3.000 26.664 ;
    END
    PORT
      LAYER M4 ;
      RECT 1.000 26.628 4.000 26.676 ;
    END
  END wd_in[49]
  PIN wd_in[50]
    DIRECTION INPUT ;
    USE SIGNAL ;
    PORT
      LAYER M4 ;
      RECT 1.000 26.784 3.000 26.808 ;
    END
    PORT
      LAYER M4 ;
      RECT 1.000 26.772 4.000 26.820 ;
    END
  END wd_in[50]
  PIN wd_in[51]
    DIRECTION INPUT ;
    USE SIGNAL ;
    PORT
      LAYER M4 ;
      RECT 1.000 26.928 3.000 26.952 ;
    END
    PORT
      LAYER M4 ;
      RECT 1.000 26.916 4.000 26.964 ;
    END
  END wd_in[51]
  PIN wd_in[52]
    DIRECTION INPUT ;
    USE SIGNAL ;
    PORT
      LAYER M4 ;
      RECT 1.000 27.072 3.000 27.096 ;
    END
    PORT
      LAYER M4 ;
      RECT 1.000 27.060 4.000 27.108 ;
    END
  END wd_in[52]
  PIN wd_in[53]
    DIRECTION INPUT ;
    USE SIGNAL ;
    PORT
      LAYER M4 ;
      RECT 1.000 27.216 3.000 27.240 ;
    END
    PORT
      LAYER M4 ;
      RECT 1.000 27.204 4.000 27.252 ;
    END
  END wd_in[53]
  PIN wd_in[54]
    DIRECTION INPUT ;
    USE SIGNAL ;
    PORT
      LAYER M4 ;
      RECT 1.000 27.360 3.000 27.384 ;
    END
    PORT
      LAYER M4 ;
      RECT 1.000 27.348 4.000 27.396 ;
    END
  END wd_in[54]
  PIN wd_in[55]
    DIRECTION INPUT ;
    USE SIGNAL ;
    PORT
      LAYER M4 ;
      RECT 1.000 27.504 3.000 27.528 ;
    END
    PORT
      LAYER M4 ;
      RECT 1.000 27.492 4.000 27.540 ;
    END
  END wd_in[55]
  PIN wd_in[56]
    DIRECTION INPUT ;
    USE SIGNAL ;
    PORT
      LAYER M4 ;
      RECT 1.000 27.648 3.000 27.672 ;
    END
    PORT
      LAYER M4 ;
      RECT 1.000 27.636 4.000 27.684 ;
    END
  END wd_in[56]
  PIN wd_in[57]
    DIRECTION INPUT ;
    USE SIGNAL ;
    PORT
      LAYER M4 ;
      RECT 1.000 27.792 3.000 27.816 ;
    END
    PORT
      LAYER M4 ;
      RECT 1.000 27.780 4.000 27.828 ;
    END
  END wd_in[57]
  PIN wd_in[58]
    DIRECTION INPUT ;
    USE SIGNAL ;
    PORT
      LAYER M4 ;
      RECT 1.000 27.936 3.000 27.960 ;
    END
    PORT
      LAYER M4 ;
      RECT 1.000 27.924 4.000 27.972 ;
    END
  END wd_in[58]
  PIN wd_in[59]
    DIRECTION INPUT ;
    USE SIGNAL ;
    PORT
      LAYER M4 ;
      RECT 1.000 28.080 3.000 28.104 ;
    END
    PORT
      LAYER M4 ;
      RECT 1.000 28.068 4.000 28.116 ;
    END
  END wd_in[59]
  PIN wd_in[60]
    DIRECTION INPUT ;
    USE SIGNAL ;
    PORT
      LAYER M4 ;
      RECT 1.000 28.224 3.000 28.248 ;
    END
    PORT
      LAYER M4 ;
      RECT 1.000 28.212 4.000 28.260 ;
    END
  END wd_in[60]
  PIN wd_in[61]
    DIRECTION INPUT ;
    USE SIGNAL ;
    PORT
      LAYER M4 ;
      RECT 1.000 28.368 3.000 28.392 ;
    END
    PORT
      LAYER M4 ;
      RECT 1.000 28.356 4.000 28.404 ;
    END
  END wd_in[61]
  PIN wd_in[62]
    DIRECTION INPUT ;
    USE SIGNAL ;
    PORT
      LAYER M4 ;
      RECT 1.000 28.512 3.000 28.536 ;
    END
    PORT
      LAYER M4 ;
      RECT 1.000 28.500 4.000 28.548 ;
    END
  END wd_in[62]
  PIN wd_in[63]
    DIRECTION INPUT ;
    USE SIGNAL ;
    PORT
      LAYER M4 ;
      RECT 1.000 28.656 3.000 28.680 ;
    END
    PORT
      LAYER M4 ;
      RECT 1.000 28.644 4.000 28.692 ;
    END
  END wd_in[63]
  PIN wd_in[64]
    DIRECTION INPUT ;
    USE SIGNAL ;
    PORT
      LAYER M4 ;
      RECT 1.000 28.800 3.000 28.824 ;
    END
    PORT
      LAYER M4 ;
      RECT 1.000 28.788 4.000 28.836 ;
    END
  END wd_in[64]
  PIN wd_in[65]
    DIRECTION INPUT ;
    USE SIGNAL ;
    PORT
      LAYER M4 ;
      RECT 1.000 28.944 3.000 28.968 ;
    END
    PORT
      LAYER M4 ;
      RECT 1.000 28.932 4.000 28.980 ;
    END
  END wd_in[65]
  PIN wd_in[66]
    DIRECTION INPUT ;
    USE SIGNAL ;
    PORT
      LAYER M4 ;
      RECT 1.000 29.088 3.000 29.112 ;
    END
    PORT
      LAYER M4 ;
      RECT 1.000 29.076 4.000 29.124 ;
    END
  END wd_in[66]
  PIN wd_in[67]
    DIRECTION INPUT ;
    USE SIGNAL ;
    PORT
      LAYER M4 ;
      RECT 1.000 29.232 3.000 29.256 ;
    END
    PORT
      LAYER M4 ;
      RECT 1.000 29.220 4.000 29.268 ;
    END
  END wd_in[67]
  PIN wd_in[68]
    DIRECTION INPUT ;
    USE SIGNAL ;
    PORT
      LAYER M4 ;
      RECT 1.000 29.376 3.000 29.400 ;
    END
    PORT
      LAYER M4 ;
      RECT 1.000 29.364 4.000 29.412 ;
    END
  END wd_in[68]
  PIN wd_in[69]
    DIRECTION INPUT ;
    USE SIGNAL ;
    PORT
      LAYER M4 ;
      RECT 1.000 29.520 3.000 29.544 ;
    END
    PORT
      LAYER M4 ;
      RECT 1.000 29.508 4.000 29.556 ;
    END
  END wd_in[69]
  PIN wd_in[70]
    DIRECTION INPUT ;
    USE SIGNAL ;
    PORT
      LAYER M4 ;
      RECT 1.000 29.664 3.000 29.688 ;
    END
    PORT
      LAYER M4 ;
      RECT 1.000 29.652 4.000 29.700 ;
    END
  END wd_in[70]
  PIN wd_in[71]
    DIRECTION INPUT ;
    USE SIGNAL ;
    PORT
      LAYER M4 ;
      RECT 1.000 29.808 3.000 29.832 ;
    END
    PORT
      LAYER M4 ;
      RECT 1.000 29.796 4.000 29.844 ;
    END
  END wd_in[71]
  PIN wd_in[72]
    DIRECTION INPUT ;
    USE SIGNAL ;
    PORT
      LAYER M4 ;
      RECT 1.000 29.952 3.000 29.976 ;
    END
    PORT
      LAYER M4 ;
      RECT 1.000 29.940 4.000 29.988 ;
    END
  END wd_in[72]
  PIN wd_in[73]
    DIRECTION INPUT ;
    USE SIGNAL ;
    PORT
      LAYER M4 ;
      RECT 1.000 30.096 3.000 30.120 ;
    END
    PORT
      LAYER M4 ;
      RECT 1.000 30.084 4.000 30.132 ;
    END
  END wd_in[73]
  PIN wd_in[74]
    DIRECTION INPUT ;
    USE SIGNAL ;
    PORT
      LAYER M4 ;
      RECT 1.000 30.240 3.000 30.264 ;
    END
    PORT
      LAYER M4 ;
      RECT 1.000 30.228 4.000 30.276 ;
    END
  END wd_in[74]
  PIN wd_in[75]
    DIRECTION INPUT ;
    USE SIGNAL ;
    PORT
      LAYER M4 ;
      RECT 1.000 30.384 3.000 30.408 ;
    END
    PORT
      LAYER M4 ;
      RECT 1.000 30.372 4.000 30.420 ;
    END
  END wd_in[75]
  PIN wd_in[76]
    DIRECTION INPUT ;
    USE SIGNAL ;
    PORT
      LAYER M4 ;
      RECT 1.000 30.528 3.000 30.552 ;
    END
    PORT
      LAYER M4 ;
      RECT 1.000 30.516 4.000 30.564 ;
    END
  END wd_in[76]
  PIN wd_in[77]
    DIRECTION INPUT ;
    USE SIGNAL ;
    PORT
      LAYER M4 ;
      RECT 1.000 30.672 3.000 30.696 ;
    END
    PORT
      LAYER M4 ;
      RECT 1.000 30.660 4.000 30.708 ;
    END
  END wd_in[77]
  PIN wd_in[78]
    DIRECTION INPUT ;
    USE SIGNAL ;
    PORT
      LAYER M4 ;
      RECT 1.000 30.816 3.000 30.840 ;
    END
    PORT
      LAYER M4 ;
      RECT 1.000 30.804 4.000 30.852 ;
    END
  END wd_in[78]
  PIN wd_in[79]
    DIRECTION INPUT ;
    USE SIGNAL ;
    PORT
      LAYER M4 ;
      RECT 1.000 30.960 3.000 30.984 ;
    END
    PORT
      LAYER M4 ;
      RECT 1.000 30.948 4.000 30.996 ;
    END
  END wd_in[79]
  PIN wd_in[80]
    DIRECTION INPUT ;
    USE SIGNAL ;
    PORT
      LAYER M4 ;
      RECT 1.000 31.104 3.000 31.128 ;
    END
    PORT
      LAYER M4 ;
      RECT 1.000 31.092 4.000 31.140 ;
    END
  END wd_in[80]
  PIN wd_in[81]
    DIRECTION INPUT ;
    USE SIGNAL ;
    PORT
      LAYER M4 ;
      RECT 1.000 31.248 3.000 31.272 ;
    END
    PORT
      LAYER M4 ;
      RECT 1.000 31.236 4.000 31.284 ;
    END
  END wd_in[81]
  PIN wd_in[82]
    DIRECTION INPUT ;
    USE SIGNAL ;
    PORT
      LAYER M4 ;
      RECT 1.000 31.392 3.000 31.416 ;
    END
    PORT
      LAYER M4 ;
      RECT 1.000 31.380 4.000 31.428 ;
    END
  END wd_in[82]
  PIN wd_in[83]
    DIRECTION INPUT ;
    USE SIGNAL ;
    PORT
      LAYER M4 ;
      RECT 1.000 31.536 3.000 31.560 ;
    END
    PORT
      LAYER M4 ;
      RECT 1.000 31.524 4.000 31.572 ;
    END
  END wd_in[83]
  PIN wd_in[84]
    DIRECTION INPUT ;
    USE SIGNAL ;
    PORT
      LAYER M4 ;
      RECT 1.000 31.680 3.000 31.704 ;
    END
    PORT
      LAYER M4 ;
      RECT 1.000 31.668 4.000 31.716 ;
    END
  END wd_in[84]
  PIN wd_in[85]
    DIRECTION INPUT ;
    USE SIGNAL ;
    PORT
      LAYER M4 ;
      RECT 1.000 31.824 3.000 31.848 ;
    END
    PORT
      LAYER M4 ;
      RECT 1.000 31.812 4.000 31.860 ;
    END
  END wd_in[85]
  PIN wd_in[86]
    DIRECTION INPUT ;
    USE SIGNAL ;
    PORT
      LAYER M4 ;
      RECT 1.000 31.968 3.000 31.992 ;
    END
    PORT
      LAYER M4 ;
      RECT 1.000 31.956 4.000 32.004 ;
    END
  END wd_in[86]
  PIN wd_in[87]
    DIRECTION INPUT ;
    USE SIGNAL ;
    PORT
      LAYER M4 ;
      RECT 1.000 32.112 3.000 32.136 ;
    END
    PORT
      LAYER M4 ;
      RECT 1.000 32.100 4.000 32.148 ;
    END
  END wd_in[87]
  PIN wd_in[88]
    DIRECTION INPUT ;
    USE SIGNAL ;
    PORT
      LAYER M4 ;
      RECT 1.000 32.256 3.000 32.280 ;
    END
    PORT
      LAYER M4 ;
      RECT 1.000 32.244 4.000 32.292 ;
    END
  END wd_in[88]
  PIN wd_in[89]
    DIRECTION INPUT ;
    USE SIGNAL ;
    PORT
      LAYER M4 ;
      RECT 1.000 32.400 3.000 32.424 ;
    END
    PORT
      LAYER M4 ;
      RECT 1.000 32.388 4.000 32.436 ;
    END
  END wd_in[89]
  PIN wd_in[90]
    DIRECTION INPUT ;
    USE SIGNAL ;
    PORT
      LAYER M4 ;
      RECT 1.000 32.544 3.000 32.568 ;
    END
    PORT
      LAYER M4 ;
      RECT 1.000 32.532 4.000 32.580 ;
    END
  END wd_in[90]
  PIN wd_in[91]
    DIRECTION INPUT ;
    USE SIGNAL ;
    PORT
      LAYER M4 ;
      RECT 1.000 32.688 3.000 32.712 ;
    END
    PORT
      LAYER M4 ;
      RECT 1.000 32.676 4.000 32.724 ;
    END
  END wd_in[91]
  PIN wd_in[92]
    DIRECTION INPUT ;
    USE SIGNAL ;
    PORT
      LAYER M4 ;
      RECT 1.000 32.832 3.000 32.856 ;
    END
    PORT
      LAYER M4 ;
      RECT 1.000 32.820 4.000 32.868 ;
    END
  END wd_in[92]
  PIN wd_in[93]
    DIRECTION INPUT ;
    USE SIGNAL ;
    PORT
      LAYER M4 ;
      RECT 1.000 32.976 3.000 33.000 ;
    END
    PORT
      LAYER M4 ;
      RECT 1.000 32.964 4.000 33.012 ;
    END
  END wd_in[93]
  PIN wd_in[94]
    DIRECTION INPUT ;
    USE SIGNAL ;
    PORT
      LAYER M4 ;
      RECT 1.000 33.120 3.000 33.144 ;
    END
    PORT
      LAYER M4 ;
      RECT 1.000 33.108 4.000 33.156 ;
    END
  END wd_in[94]
  PIN wd_in[95]
    DIRECTION INPUT ;
    USE SIGNAL ;
    PORT
      LAYER M4 ;
      RECT 1.000 33.264 3.000 33.288 ;
    END
    PORT
      LAYER M4 ;
      RECT 1.000 33.252 4.000 33.300 ;
    END
  END wd_in[95]
  PIN wd_in[96]
    DIRECTION INPUT ;
    USE SIGNAL ;
    PORT
      LAYER M4 ;
      RECT 1.000 33.408 3.000 33.432 ;
    END
    PORT
      LAYER M4 ;
      RECT 1.000 33.396 4.000 33.444 ;
    END
  END wd_in[96]
  PIN wd_in[97]
    DIRECTION INPUT ;
    USE SIGNAL ;
    PORT
      LAYER M4 ;
      RECT 1.000 33.552 3.000 33.576 ;
    END
    PORT
      LAYER M4 ;
      RECT 1.000 33.540 4.000 33.588 ;
    END
  END wd_in[97]
  PIN wd_in[98]
    DIRECTION INPUT ;
    USE SIGNAL ;
    PORT
      LAYER M4 ;
      RECT 1.000 33.696 3.000 33.720 ;
    END
    PORT
      LAYER M4 ;
      RECT 1.000 33.684 4.000 33.732 ;
    END
  END wd_in[98]
  PIN wd_in[99]
    DIRECTION INPUT ;
    USE SIGNAL ;
    PORT
      LAYER M4 ;
      RECT 1.000 33.840 3.000 33.864 ;
    END
    PORT
      LAYER M4 ;
      RECT 1.000 33.828 4.000 33.876 ;
    END
  END wd_in[99]
  PIN wd_in[100]
    DIRECTION INPUT ;
    USE SIGNAL ;
    PORT
      LAYER M4 ;
      RECT 1.000 33.984 3.000 34.008 ;
    END
    PORT
      LAYER M4 ;
      RECT 1.000 33.972 4.000 34.020 ;
    END
  END wd_in[100]
  PIN wd_in[101]
    DIRECTION INPUT ;
    USE SIGNAL ;
    PORT
      LAYER M4 ;
      RECT 1.000 34.128 3.000 34.152 ;
    END
    PORT
      LAYER M4 ;
      RECT 1.000 34.116 4.000 34.164 ;
    END
  END wd_in[101]
  PIN wd_in[102]
    DIRECTION INPUT ;
    USE SIGNAL ;
    PORT
      LAYER M4 ;
      RECT 1.000 34.272 3.000 34.296 ;
    END
    PORT
      LAYER M4 ;
      RECT 1.000 34.260 4.000 34.308 ;
    END
  END wd_in[102]
  PIN wd_in[103]
    DIRECTION INPUT ;
    USE SIGNAL ;
    PORT
      LAYER M4 ;
      RECT 1.000 34.416 3.000 34.440 ;
    END
    PORT
      LAYER M4 ;
      RECT 1.000 34.404 4.000 34.452 ;
    END
  END wd_in[103]
  PIN wd_in[104]
    DIRECTION INPUT ;
    USE SIGNAL ;
    PORT
      LAYER M4 ;
      RECT 1.000 34.560 3.000 34.584 ;
    END
    PORT
      LAYER M4 ;
      RECT 1.000 34.548 4.000 34.596 ;
    END
  END wd_in[104]
  PIN wd_in[105]
    DIRECTION INPUT ;
    USE SIGNAL ;
    PORT
      LAYER M4 ;
      RECT 1.000 34.704 3.000 34.728 ;
    END
    PORT
      LAYER M4 ;
      RECT 1.000 34.692 4.000 34.740 ;
    END
  END wd_in[105]
  PIN wd_in[106]
    DIRECTION INPUT ;
    USE SIGNAL ;
    PORT
      LAYER M4 ;
      RECT 1.000 34.848 3.000 34.872 ;
    END
    PORT
      LAYER M4 ;
      RECT 1.000 34.836 4.000 34.884 ;
    END
  END wd_in[106]
  PIN wd_in[107]
    DIRECTION INPUT ;
    USE SIGNAL ;
    PORT
      LAYER M4 ;
      RECT 1.000 34.992 3.000 35.016 ;
    END
    PORT
      LAYER M4 ;
      RECT 1.000 34.980 4.000 35.028 ;
    END
  END wd_in[107]
  PIN wd_in[108]
    DIRECTION INPUT ;
    USE SIGNAL ;
    PORT
      LAYER M4 ;
      RECT 1.000 35.136 3.000 35.160 ;
    END
    PORT
      LAYER M4 ;
      RECT 1.000 35.124 4.000 35.172 ;
    END
  END wd_in[108]
  PIN wd_in[109]
    DIRECTION INPUT ;
    USE SIGNAL ;
    PORT
      LAYER M4 ;
      RECT 1.000 35.280 3.000 35.304 ;
    END
    PORT
      LAYER M4 ;
      RECT 1.000 35.268 4.000 35.316 ;
    END
  END wd_in[109]
  PIN wd_in[110]
    DIRECTION INPUT ;
    USE SIGNAL ;
    PORT
      LAYER M4 ;
      RECT 1.000 35.424 3.000 35.448 ;
    END
    PORT
      LAYER M4 ;
      RECT 1.000 35.412 4.000 35.460 ;
    END
  END wd_in[110]
  PIN wd_in[111]
    DIRECTION INPUT ;
    USE SIGNAL ;
    PORT
      LAYER M4 ;
      RECT 1.000 35.568 3.000 35.592 ;
    END
    PORT
      LAYER M4 ;
      RECT 1.000 35.556 4.000 35.604 ;
    END
  END wd_in[111]
  PIN wd_in[112]
    DIRECTION INPUT ;
    USE SIGNAL ;
    PORT
      LAYER M4 ;
      RECT 1.000 35.712 3.000 35.736 ;
    END
    PORT
      LAYER M4 ;
      RECT 1.000 35.700 4.000 35.748 ;
    END
  END wd_in[112]
  PIN wd_in[113]
    DIRECTION INPUT ;
    USE SIGNAL ;
    PORT
      LAYER M4 ;
      RECT 1.000 35.856 3.000 35.880 ;
    END
    PORT
      LAYER M4 ;
      RECT 1.000 35.844 4.000 35.892 ;
    END
  END wd_in[113]
  PIN wd_in[114]
    DIRECTION INPUT ;
    USE SIGNAL ;
    PORT
      LAYER M4 ;
      RECT 1.000 36.000 3.000 36.024 ;
    END
    PORT
      LAYER M4 ;
      RECT 1.000 35.988 4.000 36.036 ;
    END
  END wd_in[114]
  PIN wd_in[115]
    DIRECTION INPUT ;
    USE SIGNAL ;
    PORT
      LAYER M4 ;
      RECT 1.000 36.144 3.000 36.168 ;
    END
    PORT
      LAYER M4 ;
      RECT 1.000 36.132 4.000 36.180 ;
    END
  END wd_in[115]
  PIN wd_in[116]
    DIRECTION INPUT ;
    USE SIGNAL ;
    PORT
      LAYER M4 ;
      RECT 1.000 36.288 3.000 36.312 ;
    END
    PORT
      LAYER M4 ;
      RECT 1.000 36.276 4.000 36.324 ;
    END
  END wd_in[116]
  PIN wd_in[117]
    DIRECTION INPUT ;
    USE SIGNAL ;
    PORT
      LAYER M4 ;
      RECT 1.000 36.432 3.000 36.456 ;
    END
    PORT
      LAYER M4 ;
      RECT 1.000 36.420 4.000 36.468 ;
    END
  END wd_in[117]
  PIN wd_in[118]
    DIRECTION INPUT ;
    USE SIGNAL ;
    PORT
      LAYER M4 ;
      RECT 1.000 36.576 3.000 36.600 ;
    END
    PORT
      LAYER M4 ;
      RECT 1.000 36.564 4.000 36.612 ;
    END
  END wd_in[118]
  PIN wd_in[119]
    DIRECTION INPUT ;
    USE SIGNAL ;
    PORT
      LAYER M4 ;
      RECT 1.000 36.720 3.000 36.744 ;
    END
    PORT
      LAYER M4 ;
      RECT 1.000 36.708 4.000 36.756 ;
    END
  END wd_in[119]
  PIN wd_in[120]
    DIRECTION INPUT ;
    USE SIGNAL ;
    PORT
      LAYER M4 ;
      RECT 1.000 36.864 3.000 36.888 ;
    END
    PORT
      LAYER M4 ;
      RECT 1.000 36.852 4.000 36.900 ;
    END
  END wd_in[120]
  PIN wd_in[121]
    DIRECTION INPUT ;
    USE SIGNAL ;
    PORT
      LAYER M4 ;
      RECT 1.000 37.008 3.000 37.032 ;
    END
    PORT
      LAYER M4 ;
      RECT 1.000 36.996 4.000 37.044 ;
    END
  END wd_in[121]
  PIN wd_in[122]
    DIRECTION INPUT ;
    USE SIGNAL ;
    PORT
      LAYER M4 ;
      RECT 1.000 37.152 3.000 37.176 ;
    END
    PORT
      LAYER M4 ;
      RECT 1.000 37.140 4.000 37.188 ;
    END
  END wd_in[122]
  PIN wd_in[123]
    DIRECTION INPUT ;
    USE SIGNAL ;
    PORT
      LAYER M4 ;
      RECT 1.000 37.296 3.000 37.320 ;
    END
    PORT
      LAYER M4 ;
      RECT 1.000 37.284 4.000 37.332 ;
    END
  END wd_in[123]
  PIN wd_in[124]
    DIRECTION INPUT ;
    USE SIGNAL ;
    PORT
      LAYER M4 ;
      RECT 1.000 37.440 3.000 37.464 ;
    END
    PORT
      LAYER M4 ;
      RECT 1.000 37.428 4.000 37.476 ;
    END
  END wd_in[124]
  PIN wd_in[125]
    DIRECTION INPUT ;
    USE SIGNAL ;
    PORT
      LAYER M4 ;
      RECT 1.000 37.584 3.000 37.608 ;
    END
    PORT
      LAYER M4 ;
      RECT 1.000 37.572 4.000 37.620 ;
    END
  END wd_in[125]
  PIN wd_in[126]
    DIRECTION INPUT ;
    USE SIGNAL ;
    PORT
      LAYER M4 ;
      RECT 1.000 37.728 3.000 37.752 ;
    END
    PORT
      LAYER M4 ;
      RECT 1.000 37.716 4.000 37.764 ;
    END
  END wd_in[126]
  PIN wd_in[127]
    DIRECTION INPUT ;
    USE SIGNAL ;
    PORT
      LAYER M4 ;
      RECT 1.000 37.872 3.000 37.896 ;
    END
    PORT
      LAYER M4 ;
      RECT 1.000 37.860 4.000 37.908 ;
    END
  END wd_in[127]
  PIN addr_in[0]
    DIRECTION INPUT ;
    USE SIGNAL ;
    PORT
      LAYER M4 ;
      RECT 1.000 39.120 3.000 39.144 ;
    END
    PORT
      LAYER M4 ;
      RECT 1.000 39.108 4.000 39.156 ;
    END
  END addr_in[0]
  PIN addr_in[1]
    DIRECTION INPUT ;
    USE SIGNAL ;
    PORT
      LAYER M4 ;
      RECT 1.000 39.264 3.000 39.288 ;
    END
    PORT
      LAYER M4 ;
      RECT 1.000 39.252 4.000 39.300 ;
    END
  END addr_in[1]
  PIN addr_in[2]
    DIRECTION INPUT ;
    USE SIGNAL ;
    PORT
      LAYER M4 ;
      RECT 1.000 39.408 3.000 39.432 ;
    END
    PORT
      LAYER M4 ;
      RECT 1.000 39.396 4.000 39.444 ;
    END
  END addr_in[2]
  PIN addr_in[3]
    DIRECTION INPUT ;
    USE SIGNAL ;
    PORT
      LAYER M4 ;
      RECT 1.000 39.552 3.000 39.576 ;
    END
    PORT
      LAYER M4 ;
      RECT 1.000 39.540 4.000 39.588 ;
    END
  END addr_in[3]
  PIN addr_in[4]
    DIRECTION INPUT ;
    USE SIGNAL ;
    PORT
      LAYER M4 ;
      RECT 1.000 39.696 3.000 39.720 ;
    END
    PORT
      LAYER M4 ;
      RECT 1.000 39.684 4.000 39.732 ;
    END
  END addr_in[4]
  PIN addr_in[5]
    DIRECTION INPUT ;
    USE SIGNAL ;
    PORT
      LAYER M4 ;
      RECT 1.000 39.840 3.000 39.864 ;
    END
    PORT
      LAYER M4 ;
      RECT 1.000 39.828 4.000 39.876 ;
    END
  END addr_in[5]
  PIN addr_in[6]
    DIRECTION INPUT ;
    USE SIGNAL ;
    PORT
      LAYER M4 ;
      RECT 1.000 39.984 3.000 40.008 ;
    END
    PORT
      LAYER M4 ;
      RECT 1.000 39.972 4.000 40.020 ;
    END
  END addr_in[6]
  PIN addr_in[7]
    DIRECTION INPUT ;
    USE SIGNAL ;
    PORT
      LAYER M4 ;
      RECT 1.000 40.128 3.000 40.152 ;
    END
    PORT
      LAYER M4 ;
      RECT 1.000 40.116 4.000 40.164 ;
    END
  END addr_in[7]
  PIN addr_in[8]
    DIRECTION INPUT ;
    USE SIGNAL ;
    PORT
      LAYER M4 ;
      RECT 1.000 40.272 3.000 40.296 ;
    END
    PORT
      LAYER M4 ;
      RECT 1.000 40.260 4.000 40.308 ;
    END
  END addr_in[8]
  PIN we_in
    DIRECTION INPUT ;
    USE SIGNAL ;
    PORT
      LAYER M4 ;
      RECT 1.000 41.520 3.000 41.544 ;
    END
    PORT
      LAYER M4 ;
      RECT 1.000 41.508 4.000 41.556 ;
    END
  END we_in
  PIN ce_in
    DIRECTION INPUT ;
    USE SIGNAL ;
    PORT
      LAYER M4 ;
      RECT 1.000 41.664 3.000 41.688 ;
    END
    PORT
      LAYER M4 ;
      RECT 1.000 41.652 4.000 41.700 ;
    END
  END ce_in
  PIN clk
    DIRECTION INPUT ;
    USE SIGNAL ;
    PORT
      LAYER M4 ;
      RECT 1.000 41.808 3.000 41.832 ;
    END
    PORT
      LAYER M4 ;
      RECT 1.000 41.796 4.000 41.844 ;
    END
  END clk
  PIN VSS
    DIRECTION INOUT ;
    USE GROUND ;
    PORT
      LAYER M4 ;
      RECT 0.048 0.000 66.452 0.096 ;
      RECT 0.048 0.768 66.452 0.864 ;
      RECT 0.048 1.536 66.452 1.632 ;
      RECT 0.048 2.304 66.452 2.400 ;
      RECT 0.048 3.072 66.452 3.168 ;
      RECT 0.048 3.840 66.452 3.936 ;
      RECT 0.048 4.608 66.452 4.704 ;
      RECT 0.048 5.376 66.452 5.472 ;
      RECT 0.048 6.144 66.452 6.240 ;
      RECT 0.048 6.912 66.452 7.008 ;
      RECT 0.048 7.680 66.452 7.776 ;
      RECT 0.048 8.448 66.452 8.544 ;
      RECT 0.048 9.216 66.452 9.312 ;
      RECT 0.048 9.984 66.452 10.080 ;
      RECT 0.048 10.752 66.452 10.848 ;
      RECT 0.048 11.520 66.452 11.616 ;
      RECT 0.048 12.288 66.452 12.384 ;
      RECT 0.048 13.056 66.452 13.152 ;
      RECT 0.048 13.824 66.452 13.920 ;
      RECT 0.048 14.592 66.452 14.688 ;
      RECT 0.048 15.360 66.452 15.456 ;
      RECT 0.048 16.128 66.452 16.224 ;
      RECT 0.048 16.896 66.452 16.992 ;
      RECT 0.048 17.664 66.452 17.760 ;
      RECT 0.048 18.432 66.452 18.528 ;
      RECT 0.048 19.200 66.452 19.296 ;
      RECT 0.048 19.968 66.452 20.064 ;
      RECT 0.048 20.736 66.452 20.832 ;
      RECT 0.048 21.504 66.452 21.600 ;
      RECT 0.048 22.272 66.452 22.368 ;
      RECT 0.048 23.040 66.452 23.136 ;
      RECT 0.048 23.808 66.452 23.904 ;
      RECT 0.048 24.576 66.452 24.672 ;
      RECT 0.048 25.344 66.452 25.440 ;
      RECT 0.048 26.112 66.452 26.208 ;
      RECT 0.048 26.880 66.452 26.976 ;
      RECT 0.048 27.648 66.452 27.744 ;
      RECT 0.048 28.416 66.452 28.512 ;
      RECT 0.048 29.184 66.452 29.280 ;
      RECT 0.048 29.952 66.452 30.048 ;
      RECT 0.048 30.720 66.452 30.816 ;
      RECT 0.048 31.488 66.452 31.584 ;
      RECT 0.048 32.256 66.452 32.352 ;
      RECT 0.048 33.024 66.452 33.120 ;
      RECT 0.048 33.792 66.452 33.888 ;
      RECT 0.048 34.560 66.452 34.656 ;
      RECT 0.048 35.328 66.452 35.424 ;
      RECT 0.048 36.096 66.452 36.192 ;
      RECT 0.048 36.864 66.452 36.960 ;
      RECT 0.048 37.632 66.452 37.728 ;
      RECT 0.048 38.400 66.452 38.496 ;
      RECT 0.048 39.168 66.452 39.264 ;
      RECT 0.048 39.936 66.452 40.032 ;
      RECT 0.048 40.704 66.452 40.800 ;
      RECT 0.048 41.472 66.452 41.568 ;
    END
  END VSS
  PIN VDD
    DIRECTION INOUT ;
    USE POWER ;
    PORT
      LAYER M4 ;
      RECT 0.048 0.384 66.452 0.480 ;
      RECT 0.048 1.152 66.452 1.248 ;
      RECT 0.048 1.920 66.452 2.016 ;
      RECT 0.048 2.688 66.452 2.784 ;
      RECT 0.048 3.456 66.452 3.552 ;
      RECT 0.048 4.224 66.452 4.320 ;
      RECT 0.048 4.992 66.452 5.088 ;
      RECT 0.048 5.760 66.452 5.856 ;
      RECT 0.048 6.528 66.452 6.624 ;
      RECT 0.048 7.296 66.452 7.392 ;
      RECT 0.048 8.064 66.452 8.160 ;
      RECT 0.048 8.832 66.452 8.928 ;
      RECT 0.048 9.600 66.452 9.696 ;
      RECT 0.048 10.368 66.452 10.464 ;
      RECT 0.048 11.136 66.452 11.232 ;
      RECT 0.048 11.904 66.452 12.000 ;
      RECT 0.048 12.672 66.452 12.768 ;
      RECT 0.048 13.440 66.452 13.536 ;
      RECT 0.048 14.208 66.452 14.304 ;
      RECT 0.048 14.976 66.452 15.072 ;
      RECT 0.048 15.744 66.452 15.840 ;
      RECT 0.048 16.512 66.452 16.608 ;
      RECT 0.048 17.280 66.452 17.376 ;
      RECT 0.048 18.048 66.452 18.144 ;
      RECT 0.048 18.816 66.452 18.912 ;
      RECT 0.048 19.584 66.452 19.680 ;
      RECT 0.048 20.352 66.452 20.448 ;
      RECT 0.048 21.120 66.452 21.216 ;
      RECT 0.048 21.888 66.452 21.984 ;
      RECT 0.048 22.656 66.452 22.752 ;
      RECT 0.048 23.424 66.452 23.520 ;
      RECT 0.048 24.192 66.452 24.288 ;
      RECT 0.048 24.960 66.452 25.056 ;
      RECT 0.048 25.728 66.452 25.824 ;
      RECT 0.048 26.496 66.452 26.592 ;
      RECT 0.048 27.264 66.452 27.360 ;
      RECT 0.048 28.032 66.452 28.128 ;
      RECT 0.048 28.800 66.452 28.896 ;
      RECT 0.048 29.568 66.452 29.664 ;
      RECT 0.048 30.336 66.452 30.432 ;
      RECT 0.048 31.104 66.452 31.200 ;
      RECT 0.048 31.872 66.452 31.968 ;
      RECT 0.048 32.640 66.452 32.736 ;
      RECT 0.048 33.408 66.452 33.504 ;
      RECT 0.048 34.176 66.452 34.272 ;
      RECT 0.048 34.944 66.452 35.040 ;
      RECT 0.048 35.712 66.452 35.808 ;
      RECT 0.048 36.480 66.452 36.576 ;
      RECT 0.048 37.248 66.452 37.344 ;
      RECT 0.048 38.016 66.452 38.112 ;
      RECT 0.048 38.784 66.452 38.880 ;
      RECT 0.048 39.552 66.452 39.648 ;
      RECT 0.048 40.320 66.452 40.416 ;
      RECT 0.048 41.088 66.452 41.184 ;
      RECT 0.048 41.856 66.452 41.952 ;
    END
  END VDD
  OBS
    LAYER M1 ;
    RECT 0 0 66.500 42.000 ;
    LAYER M2 ;
    RECT 0 0 66.500 42.000 ;
    LAYER M3 ;
    RECT 0 0 66.500 42.000 ;
  END
END fakeram_128x512
END LIBRARY
